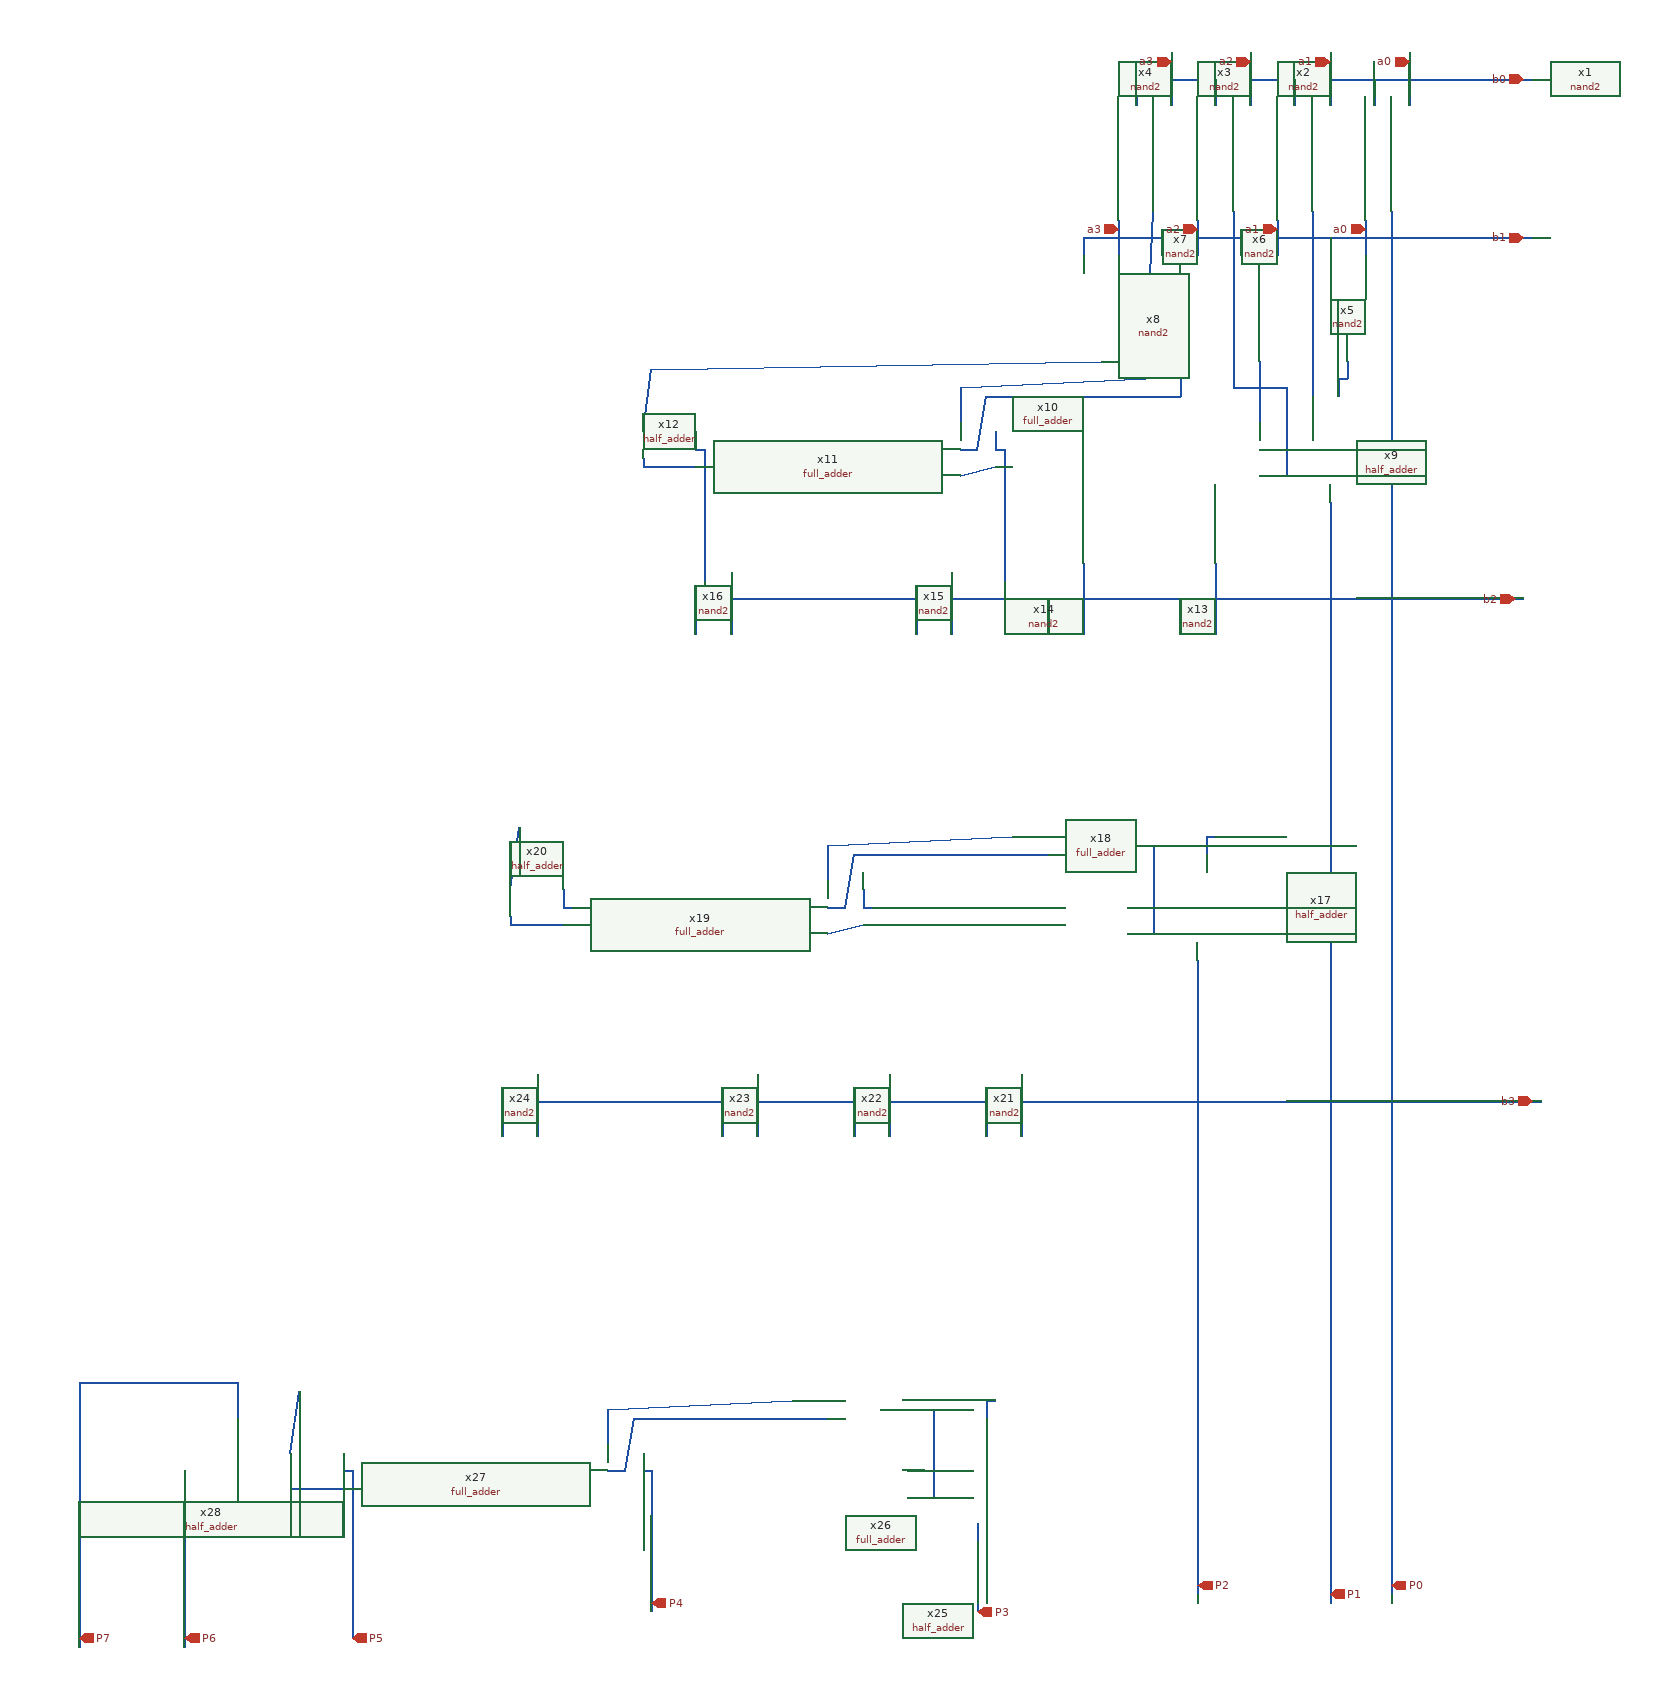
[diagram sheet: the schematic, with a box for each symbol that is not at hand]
v {xschem version=3.1.0 file_version=1.2 }
G {}
K {}
V {}
S {}
E {}
N -150 -140 -150 -110 {
lab=b0}
N -150 -140 300 -140 {
lab=b0}
N -60 -140 -60 -110 {
lab=b0}
N 30 -140 30 -110 {
lab=b0}
N 120 -140 120 -110 {
lab=b0}
N -110 -170 -110 -110 {
lab=a3}
N -20 -170 -20 -110 {
lab=a2}
N 70 -170 70 -110 {
lab=a1}
N 160 -170 160 -110 {
lab=a0}
N -210 40 -210 60 {
lab=b1}
N -210 40 300 40 {
lab=b1}
N -170 20 -170 60 {
lab=a3}
N -120 40 -120 60 {
lab=b1}
N -30 40 -30 60 {
lab=b1}
N 70 40 70 60 {
lab=b1}
N -80 20 -80 60 {
lab=a2}
N 10 20 10 60 {
lab=a1}
N 110 20 110 60 {
lab=a0}
N 140 10 140 750 {
lab=#net1}
N 50 10 50 220 {
lab=#net2}
N 90 180 90 200 {
lab=#net3}
N 80 200 90 200 {
lab=#net3}
N 80 200 80 220 {
lab=#net3}
N 70 340 70 360 {
lab=P1}
N -10 280 10 280 {
lab=#net4}
N -10 180 -10 250 {
lab=#net5}
N -40 10 -40 210 {
lab=#net6}
N -40 210 20 210 {
lab=#net6}
N 20 210 20 310 {
lab=#net6}
N -10 310 20 310 {
lab=#net6}
N -100 180 -100 220 {
lab=#net7}
N -320 220 -100 220 {
lab=#net7}
N -330 280 -320 220 {
lab=#net7}
N -350 280 -330 280 {
lab=#net7}
N -140 200 -130 10 {
lab=#net8}
N -350 210 -140 200 {
lab=#net8}
N -350 210 -350 250 {
lab=#net8}
N -350 310 -310 300 {
lab=#net9}
N -310 260 -310 280 {
lab=#net10}
N -310 280 -300 280 {
lab=#net10}
N -300 280 -300 410 {
lab=#net10}
N -710 300 -650 300 {
lab=#net11}
N -710 290 -710 300 {
lab=#net11}
N -700 190 -190 180 {
lab=#net12}
N -710 260 -700 190 {
lab=#net12}
N -650 260 -650 280 {
lab=#net13}
N -650 280 -640 280 {
lab=#net13}
N -640 280 -640 430 {
lab=#net13}
N -300 410 -300 430 {
lab=#net10}
N 70 360 70 400 {
lab=P1}
N -60 410 -60 490 {
lab=#net14}
N -210 410 -210 490 {
lab=#net15}
N -360 420 -360 490 {
lab=#net16}
N -610 420 -610 490 {
lab=#net17}
N -650 450 -650 490 {
lab=b2}
N -650 450 290 450 {
lab=b2}
N -400 450 -400 490 {
lab=b2}
N -250 450 -250 490 {
lab=b2}
N -100 460 -100 490 {
lab=b2}
N -100 450 -100 460 {
lab=b2}
N -70 720 -60 720 {
lab=#net18}
N -70 720 -70 740 {
lab=#net18}
N -80 860 -80 880 {
lab=P2}
N -160 800 -140 800 {
lab=#net19}
N -190 730 -130 730 {
lab=#net20}
N -130 730 -130 830 {
lab=#net20}
N -160 830 -130 830 {
lab=#net20}
N -470 740 -250 740 {
lab=#net21}
N -480 800 -470 740 {
lab=#net21}
N -500 800 -480 800 {
lab=#net21}
N -500 730 -290 720 {
lab=#net22}
N -500 730 -500 770 {
lab=#net22}
N -500 830 -460 820 {
lab=#net23}
N -460 780 -460 800 {
lab=#net24}
N -460 800 -450 800 {
lab=#net24}
N -860 820 -800 820 {
lab=#net25}
N -860 810 -860 820 {
lab=#net25}
N -860 780 -850 710 {
lab=#net26}
N -800 780 -800 800 {
lab=#net27}
N -800 800 -790 800 {
lab=#net27}
N -580 990 -580 1060 {
lab=#net28}
N -830 990 -830 1060 {
lab=#net29}
N -870 1020 -870 1060 {
lab=P1}
N -870 1020 70 1020 {
lab=P1}
N -620 1020 -620 1060 {
lab=P1}
N -470 1020 -470 1060 {
lab=P1}
N -320 1030 -320 1060 {
lab=P1}
N -320 1020 -320 1030 {
lab=P1}
N 70 1020 310 1020 {
lab=b3}
N -430 990 -430 1060 {
lab=#net30}
N -280 990 -280 1060 {
lab=#net31}
N -320 1360 -310 1360 {
lab=#net32}
N -320 1360 -320 1380 {
lab=#net32}
N -330 1500 -330 1520 {
lab=P3}
N -410 1440 -390 1440 {
lab=#net33}
N -440 1370 -380 1370 {
lab=#net34}
N -380 1370 -380 1470 {
lab=#net34}
N -410 1470 -380 1470 {
lab=#net34}
N -720 1380 -500 1380 {
lab=#net35}
N -730 1440 -720 1380 {
lab=#net35}
N -750 1440 -730 1440 {
lab=#net35}
N -750 1370 -540 1360 {
lab=#net36}
N -750 1370 -750 1410 {
lab=#net36}
N -710 1420 -710 1440 {
lab=P4}
N -1110 1460 -1050 1460 {
lab=#net37}
N -1110 1450 -1110 1460 {
lab=#net37}
N -1110 1420 -1100 1350 {
lab=#net38}
N -1050 1420 -1050 1440 {
lab=P5}
N -1050 1440 -1040 1440 {
lab=P5}
N -330 1500 -330 1600 {
lab=P3}
N -1040 1440 -1040 1630 {
lab=P5}
N -710 1440 -700 1440 {
lab=P4}
N -700 1440 -700 1600 {
lab=P4}
N -1170 1340 -1170 1380 {
lab=P7}
N -1350 1340 -1170 1340 {
lab=P7}
N -1350 1340 -1350 1640 {
lab=P7}
N -1230 1440 -1230 1640 {
lab=P6}
N -80 880 -80 1580 {
lab=P2}
N 140 750 140 1560 {
lab=#net1}
N 70 400 70 1580 {
lab=P1}
N 70 1580 70 1590 {
lab=P1}
N 140 1560 140 1580 {
lab=#net1}
C {NAND/nand2.sym} 140 -50 1 0 {name=x1 VSS=VSS VDD=VDD}
C {NAND/nand2.sym} 50 -50 1 0 {name=x2 VSS=VSS VDD=VDD}
C {NAND/nand2.sym} -40 -50 1 0 {name=x3 VSS=VSS VDD=VDD}
C {NAND/nand2.sym} -130 -50 1 0 {name=x4 VSS=VSS VDD=VDD}
C {NAND/nand2.sym} 90 120 1 0 {name=x5 VSS=VSS VDD=VDD}
C {NAND/nand2.sym} -10 120 1 0 {name=x6 VSS=VSS VDD=VDD}
C {NAND/nand2.sym} -100 120 1 0 {name=x7 VSS=VSS VDD=VDD}
C {NAND/nand2.sym} -190 120 1 0 {name=x8 VSS=VSS VDD=VDD}
C {devices/ipin.sym} 290 -140 2 0 {name=p3 lab=b0}
C {devices/ipin.sym} 290 40 2 0 {name=p4 lab=b1}
C {devices/ipin.sym} -110 -160 1 0 {name=p5 lab=a3}
C {devices/ipin.sym} -20 -160 1 0 {name=p6 lab=a2}
C {devices/ipin.sym} 70 -160 1 0 {name=p7 lab=a1}
C {devices/ipin.sym} 160 -160 1 0 {name=p8 lab=a0}
C {devices/ipin.sym} 110 30 1 0 {name=p9 lab=a0}
C {devices/ipin.sym} 10 30 1 0 {name=p10 lab=a1}
C {devices/ipin.sym} -80 30 1 0 {name=p11 lab=a2}
C {devices/ipin.sym} -170 30 1 0 {name=p12 lab=a3}
C {ADDER/half_adder.sym} -20 280 0 0 {name=x9}
C {devices/opin.sym} 70 1580 1 0 {name=p1 lab=P1}
C {ADDER/full_adder.sym} -160 280 0 1 {name=x10}
C {ADDER/full_adder.sym} -500 280 0 1 {name=x11}
C {ADDER/half_adder.sym} -770 190 1 0 {name=x12}
C {NAND/nand2.sym} -80 550 1 0 {name=x13 VSS=VSS VDD=VDD}
C {NAND/nand2.sym} -230 550 1 0 {name=x14 VSS=VSS VDD=VDD}
C {NAND/nand2.sym} -380 550 1 0 {name=x15 VSS=VSS VDD=VDD}
C {NAND/nand2.sym} -630 550 1 0 {name=x16 VSS=VSS VDD=VDD}
C {devices/ipin.sym} 280 450 2 0 {name=p2 lab=b2}
C {ADDER/half_adder.sym} -170 800 0 0 {name=x17}
C {ADDER/full_adder.sym} -310 800 0 1 {name=x18}
C {ADDER/full_adder.sym} -650 800 0 1 {name=x19}
C {ADDER/half_adder.sym} -920 710 1 0 {name=x20}
C {NAND/nand2.sym} -300 1120 1 0 {name=x21 VSS=VSS VDD=VDD}
C {NAND/nand2.sym} -450 1120 1 0 {name=x22 VSS=VSS VDD=VDD}
C {NAND/nand2.sym} -600 1120 1 0 {name=x23 VSS=VSS VDD=VDD}
C {NAND/nand2.sym} -850 1120 1 0 {name=x24 VSS=VSS VDD=VDD}
C {devices/ipin.sym} 300 1020 2 0 {name=p13 lab=b3}
C {ADDER/half_adder.sym} -420 1440 0 0 {name=x25}
C {ADDER/full_adder.sym} -560 1440 0 1 {name=x26}
C {ADDER/full_adder.sym} -900 1440 0 1 {name=x27}
C {ADDER/half_adder.sym} -1170 1350 1 0 {name=x28}
C {devices/opin.sym} -330 1600 1 0 {name=p14 lab=P3}
C {devices/opin.sym} -700 1590 1 0 {name=p15 lab=P4}
C {devices/opin.sym} -1040 1630 1 0 {name=p16 lab=P5}
C {devices/opin.sym} -1230 1630 1 0 {name=p17 lab=P6}
C {devices/opin.sym} -1350 1630 1 0 {name=p18 lab=P7}
C {devices/opin.sym} -80 1570 1 0 {name=p19 lab=P2}
C {devices/opin.sym} 140 1570 1 0 {name=p20 lab=P0}
